VERSION 5.8 ;
BUSBITCHARS "[]" ;
DIVIDERCHAR "/" ;

PROPERTYDEFINITIONS
  MACRO SDLpower STRING ;
  MACRO SDLground STRING ;
  MACRO SDLglobal STRING ;
END PROPERTYDEFINITIONS

VIA L1M1_C_0
  VIARULE L1M1_C ;
  CUTSIZE 0.17 0.17 ;
  LAYERS li1 mcon met1 ;
  CUTSPACING 0.19 0.19 ;
  ENCLOSURE 0 0 0.06 0.06 ;
  ROWCOL 1 1 ;
END L1M1_C_0

VIA L1M1_C_1
  VIARULE L1M1_C ;
  CUTSIZE 0.17 0.17 ;
  LAYERS li1 mcon met1 ;
  CUTSPACING 0.19 0.19 ;
  ENCLOSURE 0 0 0.06 0.06 ;
  ROWCOL 2 1 ;
END L1M1_C_1

VIA L1M1_C_2
  VIARULE L1M1_C ;
  CUTSIZE 0.17 0.17 ;
  LAYERS li1 mcon met1 ;
  CUTSPACING 0.19 0.19 ;
  ENCLOSURE 0 0 0.06 0.06 ;
  ROWCOL 1 28 ;
END L1M1_C_2

VIA L1M1_C_3
  VIARULE L1M1_C ;
  CUTSIZE 0.17 0.17 ;
  LAYERS li1 mcon met1 ;
  CUTSPACING 0.19 0.19 ;
  ENCLOSURE 0 0 0.06 0.06 ;
  ROWCOL 1 65 ;
END L1M1_C_3

VIA L1M1_C_4
  VIARULE L1M1_C ;
  CUTSIZE 0.17 0.17 ;
  LAYERS li1 mcon met1 ;
  CUTSPACING 0.19 0.19 ;
  ENCLOSURE 0 0 0.06 0.06 ;
  ROWCOL 1 15 ;
END L1M1_C_4

VIA L1M1_C_5
  VIARULE L1M1_C ;
  CUTSIZE 0.17 0.17 ;
  LAYERS li1 mcon met1 ;
  CUTSPACING 0.19 0.19 ;
  ENCLOSURE 0 0 0.06 0.06 ;
  ROWCOL 10 1 ;
END L1M1_C_5

VIA L1M1_C_6
  VIARULE L1M1_C ;
  CUTSIZE 0.17 0.17 ;
  LAYERS li1 mcon met1 ;
  CUTSPACING 0.19 0.19 ;
  ENCLOSURE 0 0 0.06 0.06 ;
  ROWCOL 75 1 ;
END L1M1_C_6

VIA L1M1_C_7
  VIARULE L1M1_C ;
  CUTSIZE 0.17 0.17 ;
  LAYERS li1 mcon met1 ;
  CUTSPACING 0.19 0.19 ;
  ENCLOSURE 0 0 0.06 0.06 ;
  ROWCOL 1 220 ;
END L1M1_C_7

VIA L1M1_C_8
  VIARULE L1M1_C ;
  CUTSIZE 0.17 0.17 ;
  LAYERS li1 mcon met1 ;
  CUTSPACING 0.19 0.19 ;
  ENCLOSURE 0 0 0.06 0.06 ;
  ROWCOL 3 1 ;
END L1M1_C_8

VIA L1M1_C_9
  VIARULE L1M1_C ;
  CUTSIZE 0.17 0.17 ;
  LAYERS li1 mcon met1 ;
  CUTSPACING 0.19 0.19 ;
  ENCLOSURE 0 0 0.06 0.06 ;
  ROWCOL 206 1 ;
END L1M1_C_9

VIA L1M1_C_10
  VIARULE L1M1_C ;
  CUTSIZE 0.17 0.17 ;
  LAYERS li1 mcon met1 ;
  CUTSPACING 0.19 0.19 ;
  ENCLOSURE 0 0 0.06 0.06 ;
  ROWCOL 106 1 ;
END L1M1_C_10

VIA L1M1_C_11
  VIARULE L1M1_C ;
  CUTSIZE 0.17 0.17 ;
  LAYERS li1 mcon met1 ;
  CUTSPACING 0.19 0.19 ;
  ENCLOSURE 0 0 0.06 0.06 ;
  ROWCOL 1 1 ;
END L1M1_C_11

VIA L1M1_C_12
  VIARULE L1M1_C ;
  CUTSIZE 0.17 0.17 ;
  LAYERS li1 mcon met1 ;
  CUTSPACING 0.19 0.19 ;
  ENCLOSURE 0 0 0.06 0.06 ;
  ROWCOL 1 360 ;
END L1M1_C_12

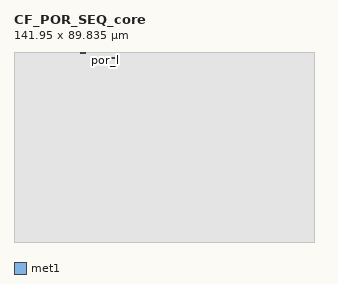
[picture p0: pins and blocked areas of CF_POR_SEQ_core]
MACRO CF_POR_SEQ_core
  ORIGIN 0 0 ;
  FOREIGN CF_POR_SEQ_core 0 0 ;
  SIZE 141.95 BY 89.835 ;
  PIN en_l
    DIRECTION INPUT ;
    USE SIGNAL ;
    PORT
      LAYER met1 ;
        RECT 42.61 89.64 42.89 89.82 ;
    END
  END en_l
  PIN por_l
    DIRECTION OUTPUT ;
    USE SIGNAL ;
    PORT
      LAYER met1 ;
        RECT 43.165 89.645 43.44 89.825 ;
    END
  END por_l
  PIN vgnd
    DIRECTION INPUT ;
    USE SIGNAL ;
    PORT
      LAYER met1 ;
        RECT 31.335 89.17 33.75 89.825 ;
    END
  END vgnd
  PIN vpwr
    DIRECTION INPUT ;
    USE SIGNAL ;
    PORT
      LAYER met1 ;
        RECT 45.45 86.75 47.96 87.31 ;
    END
  END vpwr
  OBS
    LAYER OVERLAP ;
      POLYGON  141.95 47.305  136.305 47.305  136.305 75.85  75.735 75.85  75.735 89.835  0 89.835  0 0  141.95 0 ;
    LAYER li1 ;
      RECT 0 0 141.95 89.835 ;
    LAYER met1 ;
      RECT 0 0 31.335 89.835 ;
      RECT 31.335 0 33.75 89.17 ;
      RECT 31.335 89.825 33.75 89.835 ;
      RECT 33.75 0 42.61 89.835 ;
      RECT 42.61 0 42.89 89.64 ;
      RECT 42.61 89.82 42.89 89.835 ;
      RECT 42.89 0 43.165 89.835 ;
      RECT 43.165 0 43.44 89.645 ;
      RECT 43.165 89.825 43.44 89.835 ;
      RECT 43.44 0 45.45 89.835 ;
      RECT 45.45 0 47.96 86.75 ;
      RECT 45.45 87.31 47.96 89.835 ;
      RECT 47.96 0 141.95 89.835 ;
    LAYER met2 ;
      RECT 0 0 141.95 89.835 ;
  END
  PROPERTY SDLpower "vpwr" ;
  PROPERTY SDLground "vgnd" ;
  PROPERTY SDLglobal "" ;
END CF_POR_SEQ_core

END LIBRARY
